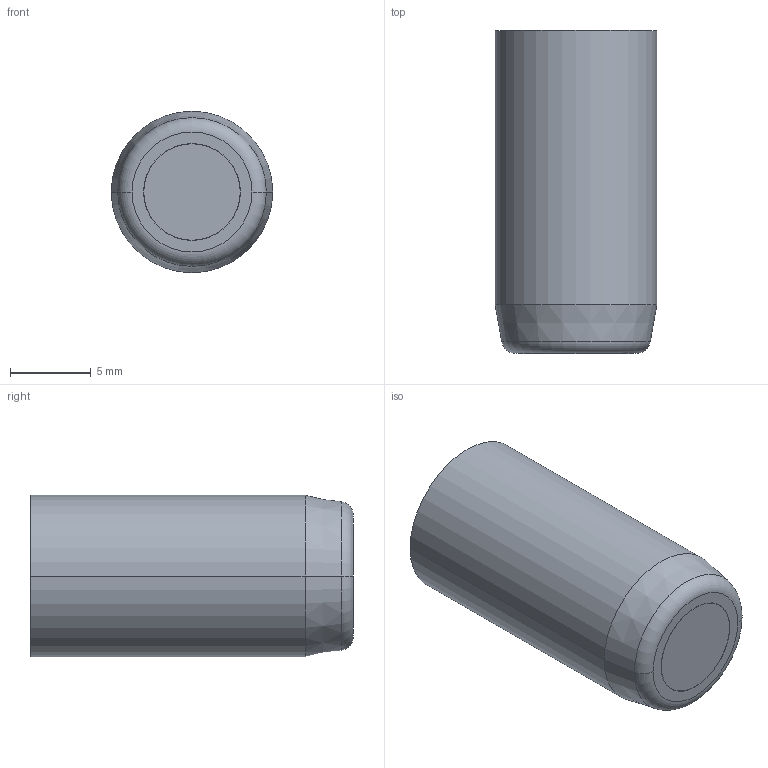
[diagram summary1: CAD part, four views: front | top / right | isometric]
STEP (ISO 10303-21) file: header records copied from the file, then geometry measured from it (millimetres).
FILE_DESCRIPTION (( 'STEP AP214' ), '1' );
FILE_NAME ('FA 105712-20.STEP', '2013-10-01T09:34:32', ( '' ), ( '' ), 'SwSTEP 2.0', 'SolidWorks 2011', '' );
FILE_SCHEMA (( 'AUTOMOTIVE_DESIGN' ));
Length unit declared in the file: millimetre
Products named in the file (6): FA 105712-20; FA 084700-2 comprimido; FA 105700-3; IA 571720; FA 105700-1; 9FA 105712
Assembly tree (5 placements, depth 2):
  FA 105712-20
    IA 571720
    9FA 105712
    FA 105700-3
    FA 084700-2 comprimido
    FA 105700-1
Bounding box: 10 x 20 x 10 mm (x, y, z)
Volume: 1394.7 mm3; surface area: 1741.2 mm2
Topology: 5 solids, 5 shells, 333 faces, 842 edges, 548 vertices
Faces by surface type: plane 151, cylinder 142, cone 24, torus 12, sphere 2, bspline 2
Entity records: 11750 total; most frequent: CARTESIAN_POINT 3199, DIRECTION 1818, ORIENTED_EDGE 1680, EDGE_CURVE 840, AXIS2_PLACEMENT_3D 675, VERTEX_POINT 548, VECTOR 468, LINE 468
One B-rep face of a CAD part: STEP entity #96.
In plain terms, the cylindrical face has radius 5 mm (diameter 10 mm), a partial arc.
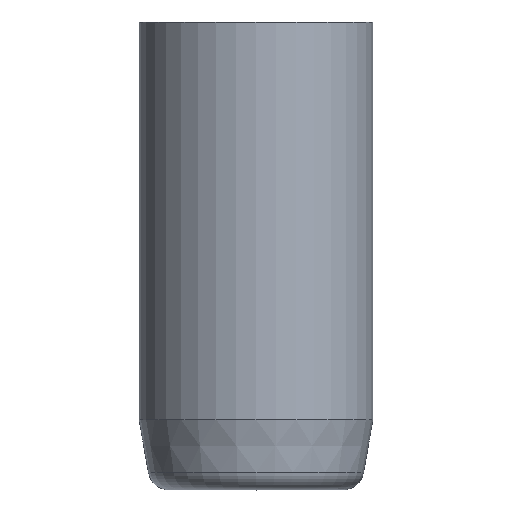
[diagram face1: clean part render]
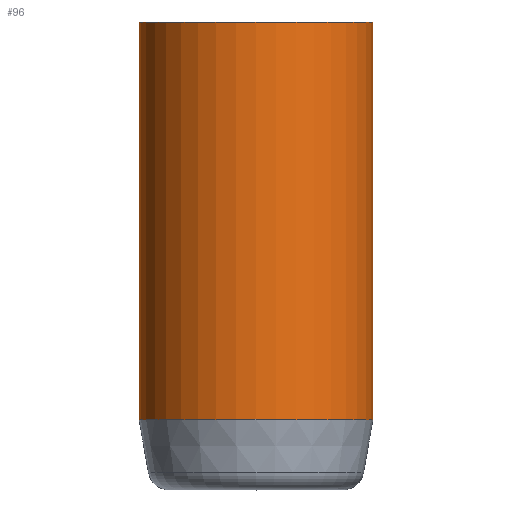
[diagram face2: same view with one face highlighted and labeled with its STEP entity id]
Its self-contained STEP definition (entity closure, numbers rounded to 3 decimals):
#96 = ADVANCED_FACE ( 'NONE', ( #440 ), #426, .T. ) ;
#426 = CYLINDRICAL_SURFACE ( 'NONE', #6603, 5. ) ;
#432 = DIRECTION ( 'NONE',  ( 0., 1., 0. ) ) ;
#433 = DIRECTION ( 'NONE',  ( 0., 0., 1. ) ) ;
#440 = FACE_OUTER_BOUND ( 'NONE', #1878, .T. ) ;
#469 = CARTESIAN_POINT ( 'NONE',  ( 0., -10.1, 0. ) ) ;
#967 = AXIS2_PLACEMENT_3D ( 'NONE', #9167, #9205, #9198 ) ;
#980 = CIRCLE ( 'NONE', #967, 5. ) ;
#1343 = AXIS2_PLACEMENT_3D ( 'NONE', #3236, #3258, #3262 ) ;
#1372 = CIRCLE ( 'NONE', #1343, 5. ) ;
#1433 = VECTOR ( 'NONE', #3281, 1000. ) ;
#1664 = ORIENTED_EDGE ( 'NONE', *, *, #9025, .T. ) ;
#1671 = ORIENTED_EDGE ( 'NONE', *, *, #9004, .T. ) ;
#1878 = EDGE_LOOP ( 'NONE', ( #10599, #10551, #1664, #1671 ) ) ;
#3236 = CARTESIAN_POINT ( 'NONE',  ( 0., 10., 0. ) ) ;
#3258 = DIRECTION ( 'NONE',  ( 0., -1., 0. ) ) ;
#3262 = DIRECTION ( 'NONE',  ( -1., 0., 0. ) ) ;
#3268 = LINE ( 'NONE', #3296, #1433 ) ;
#3281 = DIRECTION ( 'NONE',  ( 0., 1., 0. ) ) ;
#3296 = CARTESIAN_POINT ( 'NONE',  ( 0., -10.1, 5. ) ) ;
#3429 = VECTOR ( 'NONE', #6342, 1000. ) ;
#4689 = CARTESIAN_POINT ( 'NONE',  ( 0., -7., -5. ) ) ;
#4744 = CARTESIAN_POINT ( 'NONE',  ( 0., 10., 5. ) ) ;
#4754 = CARTESIAN_POINT ( 'NONE',  ( 0., 10., -5. ) ) ;
#4795 = CARTESIAN_POINT ( 'NONE',  ( 0., -7., 5. ) ) ;
#6321 = LINE ( 'NONE', #6324, #3429 ) ;
#6324 = CARTESIAN_POINT ( 'NONE',  ( 0., -10.1, -5. ) ) ;
#6342 = DIRECTION ( 'NONE',  ( 0., 1., 0. ) ) ;
#6603 = AXIS2_PLACEMENT_3D ( 'NONE', #469, #432, #433 ) ;
#8489 = EDGE_CURVE ( 'NONE', #11081, #11743, #6321, .T. ) ;
#8711 = EDGE_CURVE ( 'NONE', #11762, #11081, #980, .T. ) ;
#9004 = EDGE_CURVE ( 'NONE', #11706, #11743, #1372, .T. ) ;
#9025 = EDGE_CURVE ( 'NONE', #11762, #11706, #3268, .T. ) ;
#9167 = CARTESIAN_POINT ( 'NONE',  ( 0., -7., 0. ) ) ;
#9198 = DIRECTION ( 'NONE',  ( 0., 0., -1. ) ) ;
#9205 = DIRECTION ( 'NONE',  ( 0., -1., 0. ) ) ;
#10551 = ORIENTED_EDGE ( 'NONE', *, *, #8711, .F. ) ;
#10599 = ORIENTED_EDGE ( 'NONE', *, *, #8489, .F. ) ;
#11081 = VERTEX_POINT ( 'NONE', #4689 ) ;
#11706 = VERTEX_POINT ( 'NONE', #4744 ) ;
#11743 = VERTEX_POINT ( 'NONE', #4754 ) ;
#11762 = VERTEX_POINT ( 'NONE', #4795 ) ;
